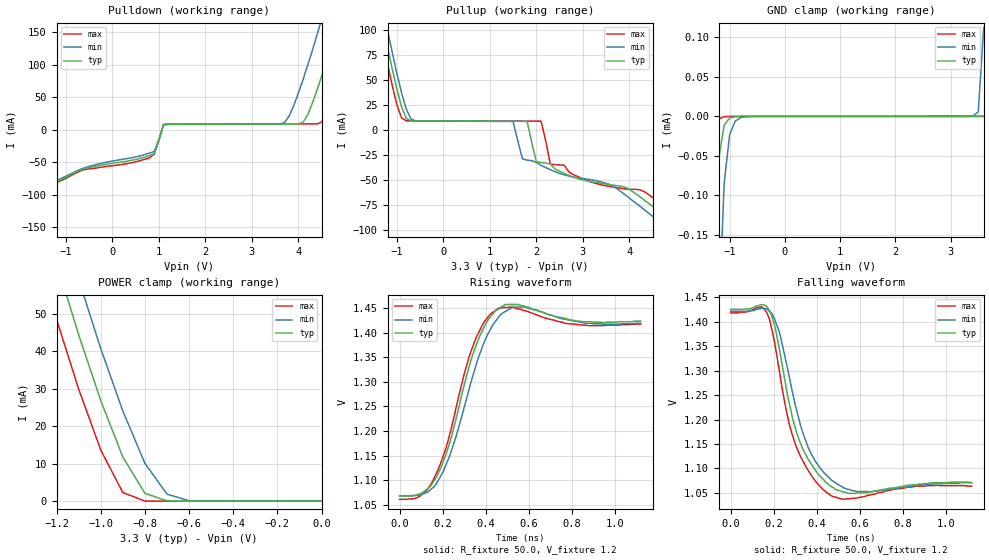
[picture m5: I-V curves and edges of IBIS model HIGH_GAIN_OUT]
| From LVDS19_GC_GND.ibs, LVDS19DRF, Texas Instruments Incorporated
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|   Driver Output Model
[Model]   HIGH_GAIN_OUT
Model_type   3-state
| Signals   Y, Z
Vmeas = 1.2V   |Reference voltage for timing measurements
Cref = 1pF   |Timing specification test load capacitance value
Rref = 50   |Note: 50 Ohm load; single ended configuration
Vref = 1.20V   |Timing specification test load voltage
|Note: 50 Ohm load; single ended configuration
| variable   typ   min   max
C_comp   1.23pF   1.21pF   1.3pF
|   typ   min   max
[Temperature Range]   25.0   -40.0   85.0
[Voltage range]   3.3V   3.0V   3.6V
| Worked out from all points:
|   slope of the pulldown table from 0 to 0.495 V, typ, clamps not added: 86.5 ohm
|   slope of the pullup table from 0 to 0.495 V, typ, clamps not added: 7.12 kohm
|   GND clamp passes 1 mA (typ) near -1.46 V on its own axis
|   POWER clamp passes 1 mA (typ) near -0.75 V on its own axis
|   rising waveform, R_fixture 50.0, V_fixture 1.2: 20-80 % time 134ps typ, 144ps min, 131ps max; typ from 1.07 V to 1.42 V
|   falling waveform, R_fixture 50.0, V_fixture 1.2: 20-80 % time 112ps typ, 121ps min, 106ps max; typ from 1.43 V to 1.07 V
[Pulldown]
|Voltage I(typ)   I(min)   I(max)
-3.3V     -161mA     -162mA     -161mA
-700mV    -62.9mA    -61.4mA    -63.9mA
800mV     -39.8mA    -35.9mA    -43.3mA
900mV     -37mA      -33.5mA    -37.6mA
1.1V      7.74mA     7.43mA     8.28mA
3.7V      8.79mA     11mA       8.85mA
4.1V      11.5mA     77.4mA     8.9mA
4.4V      60.9mA     146mA      8.99mA
4.5V      82.6mA     170mA      11.8mA
4.8V      152mA      245mA      65.5mA
5.2V      253mA      349mA      159mA
6.6V      642mA      751mA      537mA
[Pullup]
|Voltage   I(typ)   I(min)   I(max)
| Note that the[Pullup]voltage table is referenced to Vcc
| and is calculated using Vtable=Vcc - Vmeasured.
-3.3V     642mA      661mA      625mA
-1.4V     128mA      146mA      111mA
-1.3V     105mA      122mA      87.8mA
-1V       40.7mA     56.5mA     25.3mA
-800mV    11.5mA     21mA       8.99mA
1.5V      8.51mA     8.03mA     8.63mA
1.8V      8.23mA     -30.4mA    8.59mA
2.1V      -32.8mA    -35.7mA    8.5mA
2.3V      -34.2mA    -40mA      -34.5mA
3.6V      -55.1mA    -55.4mA    -57mA
4.9V      -91.1mA    -102mA     -81.4mA
6.6V      -161mA     -177mA     -146mA
[GND_clamp]
|Voltage   I(typ)   I(min)   I(max)
-3.6V     -54.5mA    -62.9mA    -46.7mA
-1.4V     -612uA     -1.29mA    -148uA
-1.3V     -215uA     -657uA     -25.6uA
-1.2V     -54.8uA    -266uA     -3.43uA
-1.1V     -11.4uA    -85uA      -426nA
-1V       -2.22uA    -23.2uA    -55.8nA
-900mV    -414nA     -5.94uA    -16.5nA
-800mV    -75.3nA    -1.52uA    -12nA
-500mV    -7.34nA    -68.1nA    -9.02nA
3.4V      426pA      344nA      314pA
3.5V      439pA      5.65uA     326pA
3.6V      487pA      113uA      337pA
[Power_clamp]
| Note that the[POWER_clamp]voltage table is referenced to Vcc
| and is calculated using Vtable=Vcc - Vmeasured.
|Voltage   I(typ)   I(min)   I(max)
-3.3V     622mA      646mA      598mA
-1.3V     84.4mA     100mA      68.9mA
-1.2V     63.8mA     79.1mA     48.6mA
-1.1V     44.5mA     59.3mA     30mA
-1V       26.9mA     40.8mA     13.7mA
-900mV    11.8mA     24.1mA     2.29mA
-800mV    2.08mA     10.1mA     37.4uA
-700mV    77.3uA     1.86mA     447nA
-600mV    2.24uA     113uA      4.65nA
0V        414pA      509pA      337pA
[Ramp]
|   typ   min   max
dV/dt_r   0.215/82ps   0.213/100ps   0.217/90ps
dV/dt_f   0.217/100ps   0.214/120ps   0.218/120ps
R_load = 50ohm |Note: The measurement is on a single-ended configuration
|   with 100ohm line-to-line.
[Rising Waveform]
R_fixture = 50.0
V_fixture = 1.2
C_fixture = 0p
L_fixture = 0n
|   V(typ)  V(min)  V(max)
0s        1.068V     1.068V     1.061V
108ps     1.075V     1.072V     1.072V
192ps     1.126V     1.109V     1.136V
264ps     1.228V     1.191V     1.25V
324ps     1.332V     1.287V     1.352V
372ps     1.393V     1.356V     1.404V
432ps     1.437V     1.415V     1.441V
528ps     1.457V     1.452V     1.451V
780ps     1.427V     1.426V     1.418V
1.12ns    1.423V     1.419V     1.417V
[Falling Waveform]
R_fixture = 50.0
V_fixture = 1.2
C_fixture = 0p
L_fixture = 0n
|   V(typ)  V(min)  V(max)
0s        1.425V     1.421V     1.418V
144ps     1.435V     1.427V     1.43V
192ps     1.41V      1.417V     1.383V
228ps     1.34V      1.376V     1.294V
264ps     1.25V      1.305V     1.207V
300ps     1.183V     1.23V      1.15V
360ps     1.119V     1.143V     1.096V
468ps     1.063V     1.076V     1.044V
648ps     1.052V     1.052V     1.046V
1.12ns    1.071V     1.071V     1.064V
